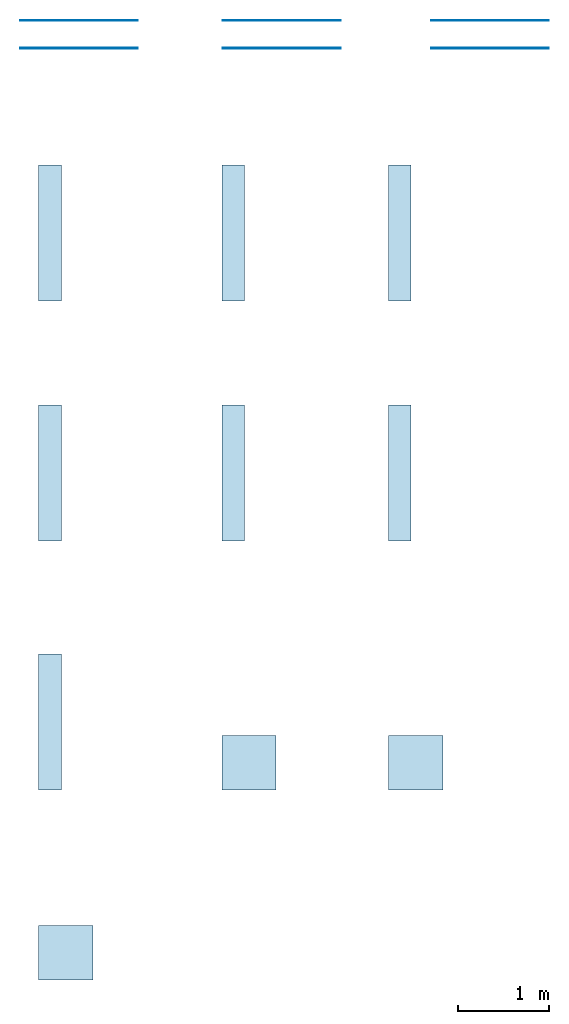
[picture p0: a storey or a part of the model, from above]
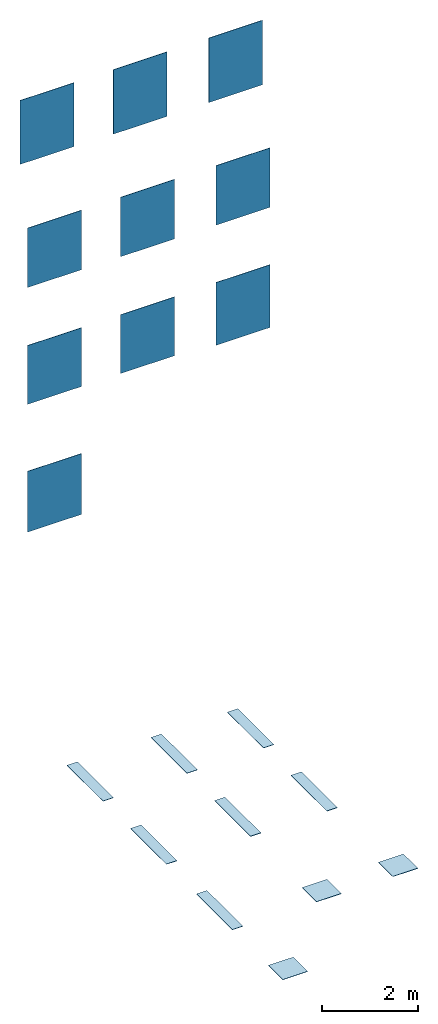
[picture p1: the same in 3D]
Properties of the parts of a building model (IFC2X3)

# File
Description: ViewDefinition [CoordinationView_V2.0], RevitIdentifiers [VersionGUID: 0e656246-f90a-4c87-a70b-e7487b4731d9, NumberOfSaves: 539], CoordinateReference [CoordinateBase: Shared Coordinates, ProjectSite: Internal]
File name: Project Number
Time: 2023-12-12T17:00:11+01:00
Written by: ODA SDAI 24.3
Made in: Autodesk Revit 24.1.11.26 (ENU) - IFC 24.1.11.26

# IfcProject, Project Number
LongName: Refin-Blended; Phase: Project Status

# IfcSite, Default
RefLatitude: 51, 30, 0, 549316; RefLongitude: 0, -7, -34, -450321; RefElevation: 0 mm

# IfcBuilding
Pset_BuildingCommon - NumberOfStoreys: 1

# IfcBuildingStorey: Level:Circle Head - Project Datum (2)
Pset_AirSideSystemInformation - sets with these values: 2
Name | LongName = Name | Elevation (mm)
Level 0 | Level 0 | 0
Level 1 | Level 1 | 4000

# IfcSlab: Floor:Floor_Tiles_Refin-Tamashi-Caviar-Matt_25x150_RA94, Floor:Floor_Tiles_Refin-Tamashi-Caviar-Matt_25x150_RA94:351397
In: Level 0
Type - PredefinedType: FLOOR; Material: Tamashi-Caviar-Matt-25x150 RA94 9 mm, <Unnamed> 1 mm
Type - Pset_ConcreteElementGeneral - FireRating: INERT
Type - Pset_ElementShading - Color: GREY
Type - Pset_FireRatingProperties - SurfaceSpreadOfFlame: INERT
Type - Pset_ManufacturerOccurrence - BarCode: N/A; SerialNumber: N/A
Type - Pset_ManufacturerTypeInformation - ArticleNumber: RA94; ModelReference: RA94; ModelLabel: TAMASHI CAVIAR MATT R 25X150; Manufacturer: info@refin.it; ProductionYear: N/A
Type - Pset_PrecastConcreteElementGeneral - SerialNumber: N/A
Type - Pset_ProductRequirements - Name: Tamashi_Caviar_Matt_25X150 R; Category: Pr_35_93_96_19:Ceramic tiles
Type - Pset_QuantityTakeOff - Reference: N/A
Type - Pset_ReinforcementBarPitchOfSlab - Description: PORCELAIN STONEWARE TILE; Reference: N/A
Type - Pset_SlabCommon - Reference: N/A; IsExternal: no; AcousticRating: N/A; FireRating: INERT; SurfaceSpreadOfFlame: INERT
Type - Pset_Warranty - WarrantyContent: N/A; Exclusions: N/A
Pset_QuantityTakeOff - sets with these values: 2
Pset_SlabCommon - LoadBearing: no; PitchAngle: 0 deg

# IfcSlab: Floor:Floor_Tiles_Refin-Tamashi-Cream-Matt_25x150_RA95, Floor:Floor_Tiles_Refin-Tamashi-Cream-Matt_25x150_RA95:363520
In: Level 0
Type - PredefinedType: FLOOR; Material: Tamashi-Cream-Matt-25x150 RA95 9 mm, <Unnamed> 1 mm
Type - Pset_ConcreteElementGeneral - FireRating: INERT
Type - Pset_ElementShading - Color: LIGHT BROWN
Type - Pset_FireRatingProperties - SurfaceSpreadOfFlame: INERT
Type - Pset_ManufacturerOccurrence - BarCode: N/A; SerialNumber: N/A
Type - Pset_ManufacturerTypeInformation - ArticleNumber: RA95; ModelReference: RA95; ModelLabel: TAMASHI CREAM MATT R 25X150; Manufacturer: info@refin.it; ProductionYear: N/A
Type - Pset_PrecastConcreteElementGeneral - SerialNumber: N/A
Type - Pset_ProductRequirements - Name: Tamashi_Cream_Matt_25X150 R; Category: Pr_35_93_96_19:Ceramic tiles
Type - Pset_QuantityTakeOff - Reference: N/A
Type - Pset_ReinforcementBarPitchOfSlab - Description: PORCELAIN STONEWARE TILE; Reference: N/A
Type - Pset_SlabCommon - Reference: N/A; IsExternal: no; AcousticRating: N/A; FireRating: INERT; SurfaceSpreadOfFlame: INERT
Type - Pset_Warranty - WarrantyContent: N/A; Exclusions: N/A
Pset_QuantityTakeOff - sets with these values: 2
Pset_SlabCommon - LoadBearing: no; PitchAngle: 0 deg

# IfcSlab: Floor:Floor_Tiles_Refin-Tamashi-Pepper-Leaf-Matt_25x150_RB13, Floor:Floor_Tiles_Refin-Tamashi-Pepper-Leaf-Matt_25x150_RB13:364341
In: Level 0
Type - PredefinedType: FLOOR; Material: Tamashi-Pepper-Leaf-Matt-60x60 RB13 9 mm, <Unnamed> 1 mm
Type - Pset_ConcreteElementGeneral - FireRating: INERT
Type - Pset_ElementShading - Color: MIX
Type - Pset_FireRatingProperties - SurfaceSpreadOfFlame: INERT
Type - Pset_ManufacturerOccurrence - BarCode: N/A; SerialNumber: N/A
Type - Pset_ManufacturerTypeInformation - ArticleNumber: RB13; ModelReference: RB13; ModelLabel: TAMASHI PEPPER LEAF MATT R 60X60; Manufacturer: info@refin.it; ProductionYear: N/A
Type - Pset_PrecastConcreteElementGeneral - SerialNumber: N/A
Type - Pset_ProductRequirements - Name: Tamashi_Pepper_Leaf_Matt_60X60 R; Category: Pr_35_93_96_19:Ceramic tiles
Type - Pset_QuantityTakeOff - Reference: N/A
Type - Pset_ReinforcementBarPitchOfSlab - Description: PORCELAIN STONEWARE TILE; Reference: N/A
Type - Pset_SlabCommon - Reference: N/A; IsExternal: no; AcousticRating: N/A; FireRating: INERT; SurfaceSpreadOfFlame: INERT
Type - Pset_Warranty - WarrantyContent: N/A; Exclusions: N/A
Pset_QuantityTakeOff - sets with these values: 2
Pset_SlabCommon - LoadBearing: no; PitchAngle: 0 deg

# IfcSlab: Floor:Floor_Tiles_Refin-Tamashi-Pepper-Matt_25x150_RA96, Floor:Floor_Tiles_Refin-Tamashi-Pepper-Matt_25x150_RA96:363731
In: Level 0
Type - PredefinedType: FLOOR; Material: Tamashi-Pepper-Matt-25x150 RA96 9 mm, <Unnamed> 1 mm
Type - Pset_ConcreteElementGeneral - FireRating: INERT
Type - Pset_ElementShading - Color: BLACK
Type - Pset_FireRatingProperties - SurfaceSpreadOfFlame: INERT
Type - Pset_ManufacturerOccurrence - BarCode: N/A; SerialNumber: N/A
Type - Pset_ManufacturerTypeInformation - ArticleNumber: RA96; ModelReference: RA96; ModelLabel: TAMASHI PEPPER MATT R 25X150; Manufacturer: info@refin.it; ProductionYear: N/A
Type - Pset_PrecastConcreteElementGeneral - SerialNumber: N/A
Type - Pset_ProductRequirements - Name: Tamashi_Pepper_Matt_25X150 R; Category: Pr_35_93_96_19:Ceramic tiles
Type - Pset_QuantityTakeOff - Reference: N/A
Type - Pset_ReinforcementBarPitchOfSlab - Description: PORCELAIN STONEWARE TILE; Reference: N/A
Type - Pset_SlabCommon - Reference: N/A; IsExternal: no; AcousticRating: N/A; FireRating: INERT; SurfaceSpreadOfFlame: INERT
Type - Pset_Warranty - WarrantyContent: N/A; Exclusions: N/A
Pset_QuantityTakeOff - sets with these values: 2
Pset_SlabCommon - LoadBearing: no; PitchAngle: 0 deg

# IfcSlab: Floor:Floor_Tiles_Refin-Tamashi-Sugar-Matt_25x150_RA97, Floor:Floor_Tiles_Refin-Tamashi-Sugar-Matt_25x150_RA97:363859
In: Level 0
Type - PredefinedType: FLOOR; Material: Tamashi-Sugar-Matt-25x150 RA97 9 mm, <Unnamed> 1 mm
Type - Pset_ConcreteElementGeneral - FireRating: INERT
Type - Pset_ElementShading - Color: WHITE
Type - Pset_FireRatingProperties - SurfaceSpreadOfFlame: INERT
Type - Pset_ManufacturerOccurrence - BarCode: N/A; SerialNumber: N/A
Type - Pset_ManufacturerTypeInformation - ArticleNumber: RA97; ModelReference: RA97; ModelLabel: TAMASHI SUGAR MATT R 25X150; Manufacturer: info@refin.it; ProductionYear: N/A
Type - Pset_PrecastConcreteElementGeneral - SerialNumber: N/A
Type - Pset_ProductRequirements - Name: Tamashi_Sugar_Matt_25X150 R; Category: Pr_35_93_96_19:Ceramic tiles
Type - Pset_QuantityTakeOff - Reference: N/A
Type - Pset_ReinforcementBarPitchOfSlab - Description: PORCELAIN STONEWARE TILE; Reference: N/A
Type - Pset_SlabCommon - Reference: N/A; IsExternal: no; AcousticRating: N/A; FireRating: INERT; SurfaceSpreadOfFlame: INERT
Type - Pset_Warranty - WarrantyContent: N/A; Exclusions: N/A
Pset_QuantityTakeOff - sets with these values: 2
Pset_SlabCommon - LoadBearing: no; PitchAngle: 0 deg

# IfcSlab: Floor:Floor_Tiles_Refin-Tamashi-Tea-Leaf-Matt_25x150_RB14, Floor:Floor_Tiles_Refin-Tamashi-Tea-Leaf-Matt_25x150_RB14:364603
In: Level 0
Type - PredefinedType: FLOOR; Material: Tamashi-Tea-Leaf-Matt-60x60 RB14 9 mm, <Unnamed> 1 mm
Type - Pset_ConcreteElementGeneral - FireRating: INERT
Type - Pset_ElementShading - Color: MIX
Type - Pset_FireRatingProperties - SurfaceSpreadOfFlame: INERT
Type - Pset_ManufacturerOccurrence - BarCode: N/A; SerialNumber: N/A
Type - Pset_ManufacturerTypeInformation - ArticleNumber: RB14; ModelReference: RB14; ModelLabel: TAMASHI TEA LEAF MATT R 60X60; Manufacturer: info@refin.it; ProductionYear: N/A
Type - Pset_PrecastConcreteElementGeneral - SerialNumber: N/A
Type - Pset_ProductRequirements - Name: Tamashi_Tea_Leaf_Matt_60X60 R; Category: Pr_35_93_96_19:Ceramic tiles
Type - Pset_QuantityTakeOff - Reference: N/A
Type - Pset_ReinforcementBarPitchOfSlab - Description: PORCELAIN STONEWARE TILE; Reference: N/A
Type - Pset_SlabCommon - Reference: N/A; IsExternal: no; AcousticRating: N/A; FireRating: INERT; SurfaceSpreadOfFlame: INERT
Type - Pset_Warranty - WarrantyContent: N/A; Exclusions: N/A
Pset_QuantityTakeOff - sets with these values: 2
Pset_SlabCommon - LoadBearing: no; PitchAngle: 0 deg

# IfcSlab: Floor:Floor_Tiles_Refin-Tamashi-Tea-Matt_25x150_RA98, Floor:Floor_Tiles_Refin-Tamashi-Tea-Matt_25x150_RA98:364026
In: Level 0
Type - PredefinedType: FLOOR; Material: Tamashi-Tea-Matt-25x150 RA98 9 mm, <Unnamed> 1 mm
Type - Pset_ConcreteElementGeneral - FireRating: INERT
Type - Pset_ElementShading - Color: BROWN
Type - Pset_FireRatingProperties - SurfaceSpreadOfFlame: INERT
Type - Pset_ManufacturerOccurrence - BarCode: N/A; SerialNumber: N/A
Type - Pset_ManufacturerTypeInformation - ArticleNumber: RA98; ModelReference: RA98; ModelLabel: TAMASHI TEA MATT R 25X150; Manufacturer: info@refin.it; ProductionYear: N/A
Type - Pset_PrecastConcreteElementGeneral - SerialNumber: N/A
Type - Pset_ProductRequirements - Name: Tamashi_Tea_Matt_25X150 R; Category: Pr_35_93_96_19:Ceramic tiles
Type - Pset_QuantityTakeOff - Reference: N/A
Type - Pset_ReinforcementBarPitchOfSlab - Description: PORCELAIN STONEWARE TILE; Reference: N/A
Type - Pset_SlabCommon - Reference: N/A; IsExternal: no; AcousticRating: N/A; FireRating: INERT; SurfaceSpreadOfFlame: INERT
Type - Pset_Warranty - WarrantyContent: N/A; Exclusions: N/A
Pset_QuantityTakeOff - sets with these values: 2
Pset_SlabCommon - LoadBearing: no; PitchAngle: 0 deg

# IfcSlab: Floor:Floor_Tiles_Refin-Tamashi-Vanilla-Matt_25x150_RA99, Floor:Floor_Tiles_Refin-Tamashi-Vanilla-Matt_25x150_RA99:364142
In: Level 0
Type - PredefinedType: FLOOR; Material: Tamashi-Vanilla-Tea-Matt-25x150 RA99 9 mm, <Unnamed> 1 mm
Type - Pset_ConcreteElementGeneral - FireRating: INERT
Type - Pset_ElementShading - Color: BEIGE
Type - Pset_FireRatingProperties - SurfaceSpreadOfFlame: INERT
Type - Pset_ManufacturerOccurrence - BarCode: N/A; SerialNumber: N/A
Type - Pset_ManufacturerTypeInformation - ArticleNumber: RA99; ModelReference: RA99; ModelLabel: TAMASHI VANILLA MATT R 25X150; Manufacturer: info@refin.it; ProductionYear: N/A
Type - Pset_PrecastConcreteElementGeneral - SerialNumber: N/A
Type - Pset_ProductRequirements - Name: Tamashi_Vanilla_Matt_25X150 R; Category: Pr_35_93_96_19:Ceramic tiles
Type - Pset_QuantityTakeOff - Reference: N/A
Type - Pset_ReinforcementBarPitchOfSlab - Description: PORCELAIN STONEWARE TILE; Reference: N/A
Type - Pset_SlabCommon - Reference: N/A; IsExternal: no; AcousticRating: N/A; FireRating: INERT; SurfaceSpreadOfFlame: INERT
Type - Pset_Warranty - WarrantyContent: N/A; Exclusions: N/A
Pset_QuantityTakeOff - sets with these values: 2
Pset_SlabCommon - LoadBearing: no; PitchAngle: 0 deg

# IfcSlab: Floor:Floor_Tiles_Refin-Tamashi-Walnut-Leaf-Matt_25x150_RB15, Floor:Floor_Tiles_Refin-Tamashi-Walnut-Leaf-Matt_25x150_RB15:365162
In: Level 0
Type - PredefinedType: FLOOR; Material: Tamashi-Walnut-Leaf-Matt-60x60 RB15 9 mm, <Unnamed> 1 mm
Type - Pset_ConcreteElementGeneral - FireRating: INERT
Type - Pset_ElementShading - Color: MIX
Type - Pset_FireRatingProperties - SurfaceSpreadOfFlame: INERT
Type - Pset_ManufacturerOccurrence - BarCode: N/A; SerialNumber: N/A
Type - Pset_ManufacturerTypeInformation - ArticleNumber: RB15; ModelReference: RB15; ModelLabel: TAMASHI WALNUT LEAF MATT R 60X60; Manufacturer: info@refin.it; ProductionYear: N/A
Type - Pset_PrecastConcreteElementGeneral - SerialNumber: N/A
Type - Pset_ProductRequirements - Name: Tamashi_Walnut_Leaf_Matt_60X60 R; Category: Pr_35_93_96_19:Ceramic tiles
Type - Pset_QuantityTakeOff - Reference: N/A
Type - Pset_ReinforcementBarPitchOfSlab - Description: PORCELAIN STONEWARE TILE; Reference: N/A
Type - Pset_SlabCommon - Reference: N/A; IsExternal: no; AcousticRating: N/A; FireRating: INERT; SurfaceSpreadOfFlame: INERT
Type - Pset_Warranty - WarrantyContent: N/A; Exclusions: N/A
Pset_QuantityTakeOff - sets with these values: 2
Pset_SlabCommon - LoadBearing: no; PitchAngle: 0 deg

# IfcSlab: Floor:Floor_Tiles_Refin-Tamashi-Walnut-Matt_25x150_RB00, Floor:Floor_Tiles_Refin-Tamashi-Walnut-Matt_25x150_RB00:364259
In: Level 0
Type - PredefinedType: FLOOR; Material: Tamashi-Walnut-Tea-Matt-25x150 RB00 9 mm, <Unnamed> 1 mm
Type - Pset_ConcreteElementGeneral - FireRating: INERT
Type - Pset_ElementShading - Color: DARK BROWN
Type - Pset_FireRatingProperties - SurfaceSpreadOfFlame: INERT
Type - Pset_ManufacturerOccurrence - BarCode: N/A; SerialNumber: N/A
Type - Pset_ManufacturerTypeInformation - ArticleNumber: RB00; ModelReference: RB00; ModelLabel: TAMASHI WALNUT MATT R 25X150; Manufacturer: info@refin.it; ProductionYear: N/A
Type - Pset_PrecastConcreteElementGeneral - SerialNumber: N/A
Type - Pset_ProductRequirements - Name: Tamashi_Walnut_Matt_25X150 R; Category: Pr_35_93_96_19:Ceramic tiles
Type - Pset_QuantityTakeOff - Reference: N/A
Type - Pset_ReinforcementBarPitchOfSlab - Description: PORCELAIN STONEWARE TILE; Reference: N/A
Type - Pset_SlabCommon - Reference: N/A; IsExternal: no; AcousticRating: N/A; FireRating: INERT; SurfaceSpreadOfFlame: INERT
Type - Pset_Warranty - WarrantyContent: N/A; Exclusions: N/A
Pset_QuantityTakeOff - sets with these values: 2
Pset_SlabCommon - LoadBearing: no; PitchAngle: 0 deg

# IfcWallStandardCase: Basic Wall:Wall_Tiles_Refin-Tamashi-Caviar-Matt_25x150_RA94, Basic Wall:Wall_Tiles_Refin-Tamashi-Caviar-Matt_25x150_RA94:334895
In: Level 0
Type - PredefinedType: STANDARD; Material: <Unnamed> 1 mm, Tamashi-Caviar-Matt-25x150 RA94 9 mm
Type - Pset_ElementShading - Color: GREY
Type - Pset_FireRatingProperties - SurfaceSpreadOfFlame: INERT
Type - Pset_ManufacturerOccurrence - BarCode: N/A; SerialNumber: N/A
Type - Pset_ManufacturerTypeInformation - ArticleNumber: RA94; ModelReference: RA94; ModelLabel: TAMASHI CAVIAR MATT R 25X150; Manufacturer: info@refin.it; ProductionYear: N/A
Type - Pset_PrecastConcreteElementGeneral - SerialNumber: N/A
Type - Pset_ProductRequirements - Name: Tamashi_Caviar_Matt_25X150 R; Category: Pr_35_93_96_19:Ceramic tiles
Type - Pset_QuantityTakeOff - Reference: N/A
Type - Pset_ReinforcementBarPitchOfWall - Description: PORCELAIN STONEWARE TILE; Reference: N/A
Type - Pset_WallCommon - Reference: N/A; IsExternal: no; AcousticRating: N/A; SurfaceSpreadOfFlame: INERT
Type - Pset_Warranty - WarrantyContent: N/A; Exclusions: N/A
Pset_QuantityTakeOff - sets with these values: 2
Pset_WallCommon - ExtendToStructure: no; LoadBearing: no

# IfcWallStandardCase: Basic Wall:Wall_Tiles_Refin-Tamashi-Cream-Matt_25x150_RA95, Basic Wall:Wall_Tiles_Refin-Tamashi-Cream-Matt_25x150_RA95:333696
In: Level 0
Type - PredefinedType: STANDARD; Material: <Unnamed> 1 mm, Tamashi-Cream-Matt-25x150 RA95 9 mm
Type - Pset_ElementShading - Color: LIGHT BROWN
Type - Pset_FireRatingProperties - SurfaceSpreadOfFlame: INERT
Type - Pset_ManufacturerOccurrence - BarCode: N/A; SerialNumber: N/A
Type - Pset_ManufacturerTypeInformation - ArticleNumber: RA95; ModelReference: RA95; ModelLabel: TAMASHI CREAM MATT R 25X150; Manufacturer: info@refin.it; ProductionYear: N/A
Type - Pset_PrecastConcreteElementGeneral - SerialNumber: N/A
Type - Pset_ProductRequirements - Name: Tamashi_Cream_Matt_25X150 R; Category: Pr_35_93_96_19:Ceramic tiles
Type - Pset_QuantityTakeOff - Reference: N/A
Type - Pset_ReinforcementBarPitchOfWall - Description: PORCELAIN STONEWARE TILE; Reference: N/A
Type - Pset_WallCommon - Reference: N/A; IsExternal: no; AcousticRating: N/A; SurfaceSpreadOfFlame: INERT
Type - Pset_Warranty - WarrantyContent: N/A; Exclusions: N/A
Pset_QuantityTakeOff - sets with these values: 2
Pset_WallCommon - ExtendToStructure: no; LoadBearing: no

# IfcWallStandardCase: Basic Wall:Wall_Tiles_Refin-Tamashi-Pepper-Leaf-Matt_60x60_RB13, Basic Wall:Wall_Tiles_Refin-Tamashi-Pepper-Leaf-Matt_60x60_RB13:341039
In: Level 0
Type - PredefinedType: STANDARD; Material: <Unnamed> 1 mm, Tamashi-Pepper-Leaf-Matt-60x60 RB13 9 mm
Type - Pset_ElementShading - Color: MIX
Type - Pset_FireRatingProperties - SurfaceSpreadOfFlame: INERT
Type - Pset_ManufacturerOccurrence - BarCode: N/A; SerialNumber: N/A
Type - Pset_ManufacturerTypeInformation - ArticleNumber: RB13; ModelReference: RB13; ModelLabel: TAMASHI PEPPER LEAF MATT R 60X60; Manufacturer: info@refin.it; ProductionYear: N/A
Type - Pset_PrecastConcreteElementGeneral - SerialNumber: N/A
Type - Pset_ProductRequirements - Name: Tamashi_Pepper_Leaf_Matt_60X60 R; Category: Pr_35_93_96_19:Ceramic tiles
Type - Pset_QuantityTakeOff - Reference: N/A
Type - Pset_ReinforcementBarPitchOfWall - Description: PORCELAIN STONEWARE TILE; Reference: N/A
Type - Pset_WallCommon - Reference: N/A; IsExternal: no; AcousticRating: N/A; SurfaceSpreadOfFlame: INERT
Type - Pset_Warranty - WarrantyContent: N/A; Exclusions: N/A
Pset_QuantityTakeOff - sets with these values: 2
Pset_WallCommon - ExtendToStructure: no; LoadBearing: no

# IfcWallStandardCase: Basic Wall:Wall_Tiles_Refin-Tamashi-Pepper-Matt_25x150_RA96, Basic Wall:Wall_Tiles_Refin-Tamashi-Pepper-Matt_25x150_RA96:334553
In: Level 0
Type - PredefinedType: STANDARD; Material: <Unnamed> 1 mm, Tamashi-Pepper-Matt-25x150 RA96 9 mm
Type - Pset_ElementShading - Color: BLACK
Type - Pset_FireRatingProperties - SurfaceSpreadOfFlame: INERT
Type - Pset_ManufacturerOccurrence - BarCode: N/A; SerialNumber: N/A
Type - Pset_ManufacturerTypeInformation - ArticleNumber: RA96; ModelReference: RA96; ModelLabel: TAMASHI PEPPER MATT R 25X150; Manufacturer: info@refin.it; ProductionYear: N/A
Type - Pset_PrecastConcreteElementGeneral - SerialNumber: N/A
Type - Pset_ProductRequirements - Name: Tamashi_Pepper_Matt_25X150 R; Category: Pr_35_93_96_19:Ceramic tiles
Type - Pset_QuantityTakeOff - Reference: N/A
Type - Pset_ReinforcementBarPitchOfWall - Description: PORCELAIN STONEWARE TILE; Reference: N/A
Type - Pset_WallCommon - Reference: N/A; IsExternal: no; AcousticRating: N/A; SurfaceSpreadOfFlame: INERT
Type - Pset_Warranty - WarrantyContent: N/A; Exclusions: N/A
Pset_QuantityTakeOff - sets with these values: 2
Pset_WallCommon - ExtendToStructure: no; LoadBearing: no

# IfcWallStandardCase: Basic Wall:Wall_Tiles_Refin-Tamashi-Sugar-Matt_25x150_RA97, Basic Wall:Wall_Tiles_Refin-Tamashi-Sugar-Matt_25x150_RA97:335038
In: Level 0
Type - PredefinedType: STANDARD; Material: <Unnamed> 1 mm, Tamashi-Sugar-Matt-25x150 RA97 9 mm
Type - Pset_ElementShading - Color: WHITE
Type - Pset_FireRatingProperties - SurfaceSpreadOfFlame: INERT
Type - Pset_ManufacturerOccurrence - BarCode: N/A; SerialNumber: N/A
Type - Pset_ManufacturerTypeInformation - ArticleNumber: RA97; ModelReference: RA97; ModelLabel: TAMASHI SUGAR MATT R 25X150; Manufacturer: info@refin.it; ProductionYear: N/A
Type - Pset_PrecastConcreteElementGeneral - SerialNumber: N/A
Type - Pset_ProductRequirements - Name: Tamashi_Sugar_Matt_25X150 R; Category: Pr_35_93_96_19:Ceramic tiles
Type - Pset_QuantityTakeOff - Reference: N/A
Type - Pset_ReinforcementBarPitchOfWall - Description: PORCELAIN STONEWARE TILE; Reference: N/A
Type - Pset_WallCommon - Reference: N/A; IsExternal: no; AcousticRating: N/A; SurfaceSpreadOfFlame: INERT
Type - Pset_Warranty - WarrantyContent: N/A; Exclusions: N/A
Pset_QuantityTakeOff - sets with these values: 2
Pset_WallCommon - ExtendToStructure: no; LoadBearing: no

# IfcWallStandardCase: Basic Wall:Wall_Tiles_Refin-Tamashi-Tea-Leaf-Matt_60x60_RB14, Basic Wall:Wall_Tiles_Refin-Tamashi-Tea-Leaf-Matt_60x60_RB14:345329
In: Level 0
Type - PredefinedType: STANDARD; Material: <Unnamed> 1 mm, Tamashi-Tea-Leaf-Matt-60x60 RB14 9 mm
Type - Pset_ElementShading - Color: MIX
Type - Pset_FireRatingProperties - SurfaceSpreadOfFlame: INERT
Type - Pset_ManufacturerOccurrence - BarCode: N/A; SerialNumber: N/A
Type - Pset_ManufacturerTypeInformation - ArticleNumber: RB14; ModelReference: RB14; ModelLabel: TAMASHI TEA LEAF MATT R 60X60; Manufacturer: info@refin.it; ProductionYear: N/A
Type - Pset_PrecastConcreteElementGeneral - SerialNumber: N/A
Type - Pset_ProductRequirements - Name: Tamashi_Tea_Leaf_Matt_60X60 R; Category: Pr_35_93_96_19:Ceramic tiles
Type - Pset_QuantityTakeOff - Reference: N/A
Type - Pset_ReinforcementBarPitchOfWall - Description: PORCELAIN STONEWARE TILE; Reference: N/A
Type - Pset_WallCommon - Reference: N/A; IsExternal: no; AcousticRating: N/A; SurfaceSpreadOfFlame: INERT
Type - Pset_Warranty - WarrantyContent: N/A; Exclusions: N/A
Pset_QuantityTakeOff - sets with these values: 2
Pset_WallCommon - ExtendToStructure: no; LoadBearing: no

# IfcWallStandardCase: Basic Wall:Wall_Tiles_Refin-Tamashi-Tea-Matt_25x150_RA98, Basic Wall:Wall_Tiles_Refin-Tamashi-Tea-Matt_25x150_RA98:335490
In: Level 0
Type - PredefinedType: STANDARD; Material: <Unnamed> 1 mm, Tamashi-Tea-Matt-25x150 RA98 9 mm
Type - Pset_ElementShading - Color: BROWN
Type - Pset_FireRatingProperties - SurfaceSpreadOfFlame: INERT
Type - Pset_ManufacturerOccurrence - BarCode: N/A; SerialNumber: N/A
Type - Pset_ManufacturerTypeInformation - ArticleNumber: RA98; ModelReference: RA98; ModelLabel: TAMASHI TEA MATT R 25X150; Manufacturer: info@refin.it; ProductionYear: N/A
Type - Pset_PrecastConcreteElementGeneral - SerialNumber: N/A
Type - Pset_ProductRequirements - Name: Tamashi_Tea_Matt_25X150 R; Category: Pr_35_93_96_19:Ceramic tiles
Type - Pset_QuantityTakeOff - Reference: N/A
Type - Pset_ReinforcementBarPitchOfWall - Description: PORCELAIN STONEWARE TILE; Reference: N/A
Type - Pset_WallCommon - Reference: N/A; IsExternal: no; AcousticRating: N/A; SurfaceSpreadOfFlame: INERT
Type - Pset_Warranty - WarrantyContent: N/A; Exclusions: N/A
Pset_QuantityTakeOff - sets with these values: 2
Pset_WallCommon - ExtendToStructure: no; LoadBearing: no

# IfcWallStandardCase: Basic Wall:Wall_Tiles_Refin-Tamashi-Vanilla-Matt_25x150_RA99, Basic Wall:Wall_Tiles_Refin-Tamashi-Vanilla-Matt_25x150_RA99:335882
In: Level 0
Type - PredefinedType: STANDARD; Material: <Unnamed> 1 mm, Tamashi-Vanilla-Tea-Matt-25x150 RA99 9 mm
Type - Pset_ElementShading - Color: BEIGE
Type - Pset_FireRatingProperties - SurfaceSpreadOfFlame: INERT
Type - Pset_ManufacturerOccurrence - BarCode: N/A; SerialNumber: N/A
Type - Pset_ManufacturerTypeInformation - ArticleNumber: RA99; ModelReference: RA99; ModelLabel: TAMASHI VANILLA MATT R 25X150; Manufacturer: info@refin.it; ProductionYear: N/A
Type - Pset_PrecastConcreteElementGeneral - SerialNumber: N/A
Type - Pset_ProductRequirements - Name: Tamashi_Vanilla_Matt_25X150 R; Category: Pr_35_93_96_19:Ceramic tiles
Type - Pset_QuantityTakeOff - Reference: N/A
Type - Pset_ReinforcementBarPitchOfWall - Description: PORCELAIN STONEWARE TILE; Reference: N/A
Type - Pset_WallCommon - Reference: N/A; IsExternal: no; AcousticRating: N/A; SurfaceSpreadOfFlame: INERT
Type - Pset_Warranty - WarrantyContent: N/A; Exclusions: N/A
Pset_QuantityTakeOff - sets with these values: 2
Pset_WallCommon - ExtendToStructure: no; LoadBearing: no

# IfcWallStandardCase: Basic Wall:Wall_Tiles_Refin-Tamashi-Walnut-Leaf-Matt_60x60_RB15, Basic Wall:Wall_Tiles_Refin-Tamashi-Walnut-Leaf-Matt_60x60_RB15:345722
In: Level 0
Type - PredefinedType: STANDARD; Material: <Unnamed> 1 mm, Tamashi-Walnut-Leaf-Matt-60x60 RB15 9 mm
Type - Pset_ElementShading - Color: MIX
Type - Pset_FireRatingProperties - SurfaceSpreadOfFlame: INERT
Type - Pset_ManufacturerOccurrence - BarCode: N/A; SerialNumber: N/A
Type - Pset_ManufacturerTypeInformation - ArticleNumber: RB15; ModelReference: RB15; ModelLabel: TAMASHI WALNUT LEAF MATT R 60X60; Manufacturer: info@refin.it; ProductionYear: N/A
Type - Pset_PrecastConcreteElementGeneral - SerialNumber: N/A
Type - Pset_ProductRequirements - Name: Tamashi_Walnut_Leaf_Matt_60X60 R; Category: Pr_35_93_96_19:Ceramic tiles
Type - Pset_QuantityTakeOff - Reference: N/A
Type - Pset_ReinforcementBarPitchOfWall - Description: PORCELAIN STONEWARE TILE; Reference: N/A
Type - Pset_WallCommon - Reference: N/A; IsExternal: no; AcousticRating: N/A; SurfaceSpreadOfFlame: INERT
Type - Pset_Warranty - WarrantyContent: N/A; Exclusions: N/A
Pset_QuantityTakeOff - sets with these values: 2
Pset_WallCommon - ExtendToStructure: no; LoadBearing: no

# IfcWallStandardCase: Basic Wall:Wall_Tiles_Refin-Tamashi-Walnut-Matt_25x150_RB00, Basic Wall:Wall_Tiles_Refin-Tamashi-Walnut-Matt_25x150_RB00:341849
In: Level 0
Type - PredefinedType: STANDARD; Material: <Unnamed> 1 mm, Tamashi-Walnut-Tea-Matt-25x150 RB00 9 mm
Type - Pset_ElementShading - Color: DARK BROWN
Type - Pset_FireRatingProperties - SurfaceSpreadOfFlame: INERT
Type - Pset_ManufacturerOccurrence - BarCode: N/A; SerialNumber: N/A
Type - Pset_ManufacturerTypeInformation - ArticleNumber: RB00; ModelReference: RB00; ModelLabel: TAMASHI WALNUT MATT R 25X150; Manufacturer: info@refin.it; ProductionYear: N/A
Type - Pset_PrecastConcreteElementGeneral - SerialNumber: N/A
Type - Pset_ProductRequirements - Name: Tamashi_Walnut_Matt_25X150 R; Category: Pr_35_93_96_19:Ceramic tiles
Type - Pset_QuantityTakeOff - Reference: N/A
Type - Pset_ReinforcementBarPitchOfWall - Description: PORCELAIN STONEWARE TILE; Reference: N/A
Type - Pset_WallCommon - Reference: N/A; IsExternal: no; AcousticRating: N/A; SurfaceSpreadOfFlame: INERT
Type - Pset_Warranty - WarrantyContent: N/A; Exclusions: N/A
Pset_QuantityTakeOff - sets with these values: 2
Pset_WallCommon - ExtendToStructure: no; LoadBearing: no
